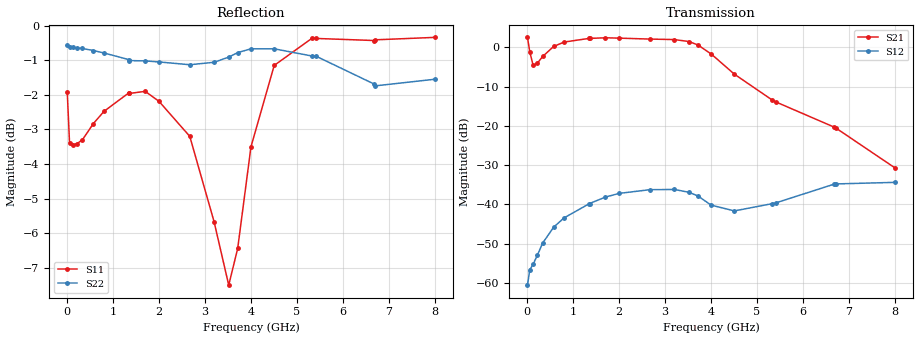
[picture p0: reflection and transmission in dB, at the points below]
!Keysight Technologies,N5244B,MY57181157,A.18.40.03
!Date: Thursday, September 18, 2025 14:36:08
!Correction: S11(C  2-Port  )
!S21(C  2-Port  )
!S12(C  2-Port  )
!S22(C  2-Port  )
!S2P File: Measurements: S11, S21, S12, S22:
# Hz S  dB  R 50
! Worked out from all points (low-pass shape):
!   7991 points, 10 MHz to 8 GHz, reference 50 ohm
!   highest |S21| = 2.50 dB at 10 MHz (marker M1); lowest = -30.7 dB at 8 GHz (marker M2)
!   |S21| within 3 dB of the highest: start of sweep to 51.23 MHz; 495.6 MHz to 3.867 GHz (3.371 GHz wide, 155 % of centre)
!   lowest |S11| = -7.5 dB at 3.521 GHz (marker M3), VSWR 2.46, Z = 21.2 + j9.51 ohm
!   |S11| at or under -10 dB: nowhere
!   |S22| runs from -1.9 to -0.5 dB; largest |S21 - S12| = 1.3
!   S11 on the Smith chart (normalised r, x): 10 MHz: 9.09, -0.64; 1.36 GHz: 0.13, -0.42; 3.716 GHz: 0.36, +0.07; 5.414 GHz: 0.02, +0.05; 6.712 GHz: 0.02, +0.15; 8 GHz: 0.02, +0.30
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1e7  -1.91 -0.9  2.50 122.0  -60.52 53.8  -0.55 -153.8
6e7  -3.39 -8.1  -1.16 136.7  -56.63 19.9  -0.63 -175.6
1.33e8  -3.44 -17.8  -4.63 162.4  -55.20 34.8  -0.63 -177.7
2.23e8  -3.41 -30.7  -4.11 -179.9  -52.96 52.1  -0.65 -178.1
3.4e8  -3.30 -44.1  -2.36 -175.1  -49.83 53.1  -0.66 -178.2
5.79e8  -2.83 -73.0  0.19 175.6  -45.79 53.5  -0.72 -177.3
8.07e8  -2.48 -94.2  1.31 162.1  -43.40 49.5  -0.79 -176.3
1.342e9  -1.95 -132.7  2.23 130.9  -39.89 41.2  -0.98 -175.1
1.36e9  -1.96 -134.1  2.24 129.9  -39.76 40.5  -1.01 -175.0
1.706e9  -1.90 -156.1  2.40 110.8  -38.12 28.5  -1.02 -175.2
2.006e9  -2.19 -175.6  2.31 94.2  -37.18 17.6  -1.05 -176.1
2.674e9  -3.20 149.8  2.07 57.7  -36.24 -14.3  -1.13 179.9
3.203e9  -5.67 138.1  1.94 24.9  -36.19 -50.3  -1.06 177.5
3.521e9  -7.50 154.1  1.45 -0.4  -36.90 -83.8  -0.91 177.3
3.716e9  -6.44 170.2  0.57 -17.4  -37.85 -108.9  -0.78 177.2
4.005e9  -3.50 177.4  -1.73 -40.4  -40.18 -151.0  -0.67 177.1
4.51e9  -1.15 174.0  -6.87 -65.4  -41.64 152.2  -0.67 179.2
5.337e9  -0.36 174.3  -13.48 -80.9  -39.78 112.5  -0.88 -175.8
5.414e9  -0.37 174.4  -13.94 -81.9  -39.58 111.4  -0.88 -175.4
6.669e9  -0.43 163.6  -20.28 -107.3  -34.87 81.5  -1.68 169.2
6.712e9  -0.41 162.8  -20.53 -108.5  -34.78 79.6  -1.74 167.9
8e9  -0.34 146.9  -30.70 -138.2  -34.38 55.3  -1.55 138.5
